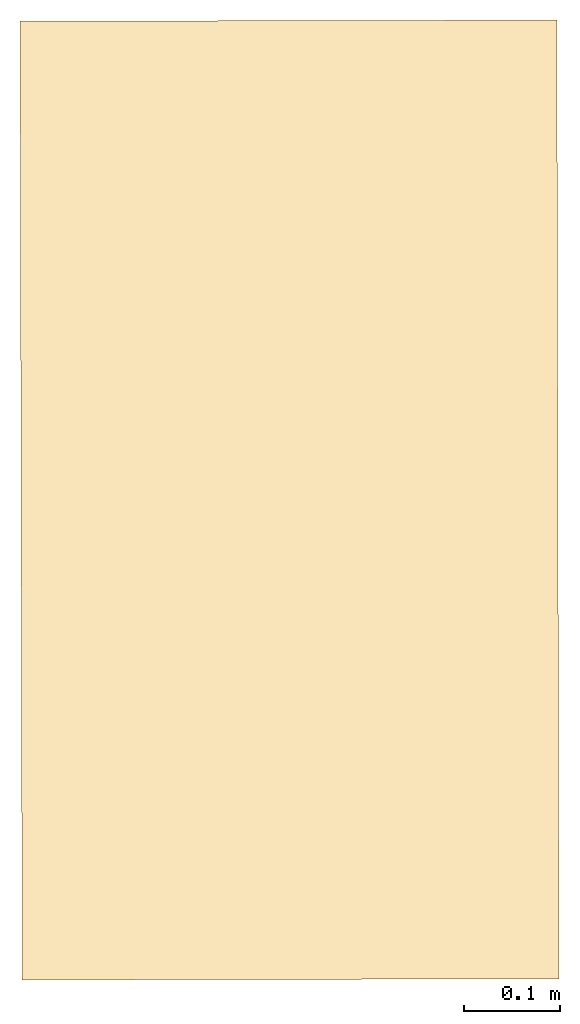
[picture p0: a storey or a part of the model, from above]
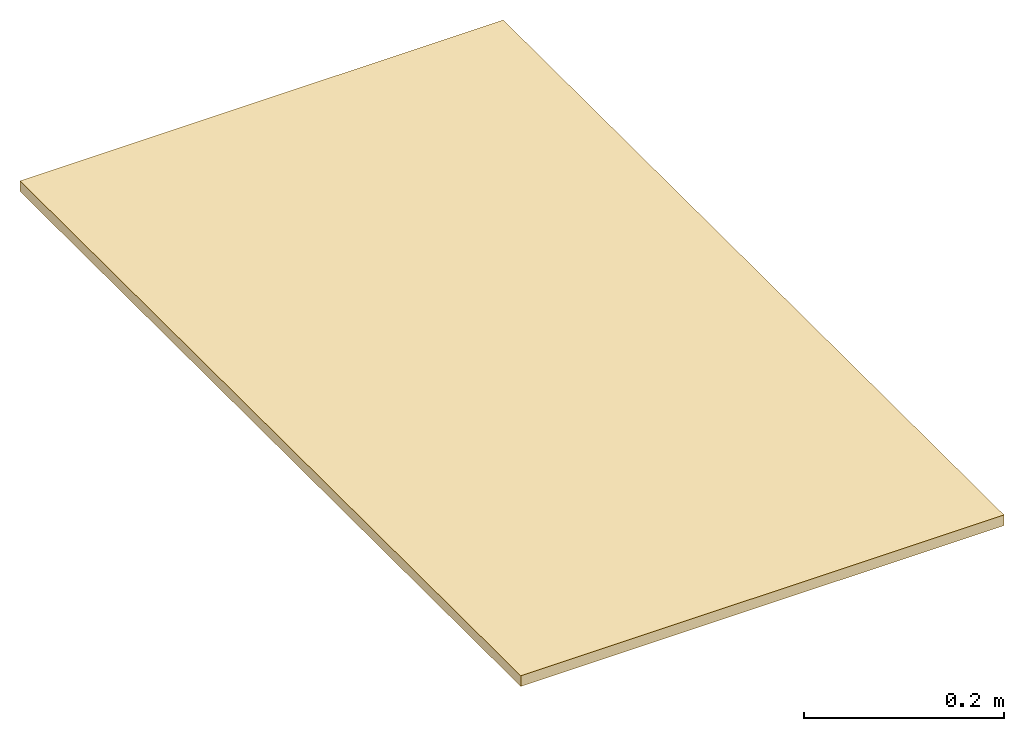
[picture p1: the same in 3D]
Properties of the parts of a building model (IFC4)

# File
Description: ViewDefinition [ReferenceView_V1.2], RevitIdentifiers [ContentGUID: d45b1106-0c7a-46e1-869b-c6a7bbcc7ea5, VersionGUID: 118b0530-1591-4ac2-8939-a10ffb714872, NumberOfSaves: 70], CoordinateReference [CoordinateBase: Internal Origin, ProjectSite: Internal], ExchangeRequirement [Architecture]
File name: 3dv__Detail__15__206+207, WS25 Wall., WS25_A_DE_25_VA_1.ifc
Time: 2025-12-19T14:28:46+01:00
Written by: ODA SDAI 25.12
Made in: Autodesk - Revit 26.3.0.37 (ENU) - 26.4.1.0

# IfcSite, Default
RefLatitude: 45, 45, 37, 23925; RefLongitude: 21, 14, 26, 780090; RefElevation: 0 cm

# IfcBuildingStorey (10)
Name | LongName | Elevation (cm)
B2__ABOVE Slab | B2__ABOVE Slab | -612
B1__ABOVE Slab | B1__ABOVE Slab | -312
L00__ABOVE Slab | L00__ABOVE Slab | -12
L01__ABOVE Slab | L01__ABOVE Slab | 273
L02__ABOVE Slab | L02__ABOVE Slab | 558
L03__ABOVE Slab | L03__ABOVE Slab | 843
L04__ABOVE Slab | L04__ABOVE Slab | 1128
L05__ABOVE Slab | L05__ABOVE Slab | 1413
L06__ABOVE Slab | L06__ABOVE Slab | 1698
L07__ABOVE Slab | L07__ABOVE Slab | 1983

# IfcBeam: Structural Framing : Leichter Stahl Trockenbau : C 50 x 30 (2)
In: L00__ABOVE Slab
Type - PredefinedType: BEAM; Material: Metal - Steel - 345 MPa

# IfcColumn: Columns : wll__TIMBER CORE__Triqbriq__lb : WS15
In: L00__ABOVE Slab
Type - PredefinedType: COLUMN; Material: <Unnamed>

# IfcColumn: Columns : wll_s__TIMBER BLOCK__Triqbriq, Full Width__wp : WS15 (6)
In: L00__ABOVE Slab
Type - PredefinedType: COLUMN; Material: _MASONRY__Timber Block__Triqbriq, X, _MASONRY__Timber Block__Triqbriq, Y

# IfcColumn: Columns : wll_s__TIMBER BLOCK__Triqbriq, Half Width__wp : WS15 (4)
In: L00__ABOVE Slab
Type - PredefinedType: COLUMN; Material: _MASONRY__Timber Block__Triqbriq, X, _MASONRY__Timber Block__Triqbriq, Y

# IfcCovering: Ceilings : Compound Ceiling : clg__INT COVERING__, GB 1.5cm__12.5(A) 3
In: B2__ABOVE Slab
Type - PredefinedType: CEILING
Classification: A 6.1.2.1 Plafoane gips-carton, placi cu cerinte standard (Uniformat); Material: _WLL & CLG FINISHES__Lime - CEM Plaster

# IfcDistributionPort (8)
Description: Flow; FlowDirection: SOURCEANDSINK; PredefinedType: PIPE; SystemType: HEATING
Name | Group
Port_41198656_0 | Hydronic Supply 2
Port_41198656_1 | Hydronic Supply 2
Port_41198681_0 | Hydronic Supply 1
Port_41198681_1 | Hydronic Supply 1
Port_41598727_0 | Hydronic Supply 3
Port_41598727_1 | Hydronic Supply 3
Port_41598729_0 | Hydronic Supply 4
Port_41598729_1 | Hydronic Supply 4

# IfcDistributionSystem: Hydronic Supply (4)
PredefinedType: HEATING
Name
Hydronic Supply 2
Hydronic Supply 1
Hydronic Supply 3
Hydronic Supply 4

# IfcPipeSegment: Pipes : Pipe Types : Default (4)
In: L00__ABOVE Slab
Name (Pipes : Pipe Types :...) | Group
 Default | Hydronic Supply 2
 Default | Hydronic Supply 1
 Default | Hydronic Supply 3
 Default | Hydronic Supply 4

# IfcSlab: Floors : Floor : flr__INT COVERING__Terrazzo Flooring, WP, Floating CEM Screed, EPS A120 9cm TRIQBRIQ
In: L00__ABOVE Slab
Type - PredefinedType: FLOOR; Material: _FLR COVERING__Terrazzo Tiles, R10, _FLR COVERING__Adhesive-fixed Terrazzo Flooring__CEM C2 S1/S2, _FLR LAYERS__WP Membrane__Syntetic Resin__Mapegum WPS, _FLR LAYERS__Screed, SL 0.5%__Semi-dry CEM, Rc ≥ 22.5 N/mm², _FLR LAYERS__Insulation__EPS 120__Austrotherm EPS A120, _FCD VENT LAYERS__Support Board__OSB 3
Classification: A 8.1.3.2 Pardoseli reci pe suport de sapa flotanta (Uniformat)

# IfcSlab: Floors : Floor : flr__STRUCTURE__Wood Beams 15cm__TriqBriq
In: L00__ABOVE Slab
Type - PredefinedType: FLOOR; Material: _STRUCTURE__Wood
Classification: S 1.2 Plansee si acoperisuri terasa (Uniformat)

# IfcWall: Columns : wll_s__DECOUPLING BEAM__Rectangular__wp : Wood
In: B1__ABOVE Slab
Type - PredefinedType: SOLIDWALL; Material: _STRUCTURE__Wood Solid
Classification: A 1.0.3 (Uniformat)

# IfcWall: Columns : wll_s__TIMBER BLOCK__Triqbriq, Full Width__wp1 : WS25 2 (9)
Type - PredefinedType: SOLIDWALL; Material: Miscellaneous__Timber Block__Triqbriq, Y
Classification: A 1.0.1 (Uniformat)
Name (Columns : wll_s__TIMBER BLOCK__Triqbriq, Full Width__wp1 :...) | In
6 x  WS25 2 | L00__ABOVE Slab
3 x  WS25 2 | B1__ABOVE Slab

# IfcWall: Columns : wll_s__TIMBER BLOCK__Triqbriq, Half Width__wp1 : WS25 2 (6)
Type - PredefinedType: SOLIDWALL; Material: Miscellaneous__Timber Block__Triqbriq, Y
Classification: A 1.0.1 (Uniformat)
Name (Columns : wll_s__TIMBER BLOCK__Triqbriq, Half Width__wp1 :...) | In
4 x  WS25 2 | L00__ABOVE Slab
2 x  WS25 2 | B1__ABOVE Slab

# IfcWall: Walls : Basic Wall : wll__EXT ENCLOSURE__Spritzkork, Wood Insulation 8.4cm__TriqBriq, FS.1
In: L00__ABOVE Slab
Type - PredefinedType: STANDARD; Material: _FCD FINISH__Mineral Render__Combed, H L/O__Capatect Kreativeffekt "Filigrano"__White, _STRUCTURE__Wood Solid, _FCD LAYERS__Insulation__Wood-fiber__Steico
Classification: A 4.3.4.2.1 Pereti exteriori (Uniformat)

# IfcWall: Walls : Basic Wall : wll__INT FINISH__Lime - CEM Plaster 2cm (2)
In: L00__ABOVE Slab
Type - PredefinedType: STANDARD; Material: _WLL & CLG FINISHES__Lime - CEM Plaster
Classification: A 7.1.1 Tencuieli umede (Uniformat)

# IfcWall: Walls : Basic Wall : wll__INT PARTITION__3-Ply Wood 2.7cm__TriqBriq, CI.1
In: L00__ABOVE Slab
Type - PredefinedType: STANDARD
Classification: A 5.4.2 Pereti PAL / MDF (Uniformat); Material: _FCD VENT LAYERS__Support Board__3-Layered Wood Board

# IfcWall: Walls : Basic Wall : wll__INT SHAFT__GB, Indep 7.5cm__12.5(H2+A) + CW50@60 / GW50
In: L00__ABOVE Slab
Type - PredefinedType: STANDARD; Material: _PB__GB__Moisture Resistant__Type H2, _PB__GB__Standard__Type A, _PB STUDS & ANC__MTL Studs__50mm__CW 50@60 / GW50
Classification: A 5.3.2.2 Tencuieli uscate gips-carton, placi cu cerinte de rezistenta la umiditate (Uniformat)

# IfcWall: Walls : Basic Wall : wll__INT SHAFT__GB, Indep 7.5cm__12.5(H2+A) + CW50@60 / GW50 2
In: L00__ABOVE Slab
Type - PredefinedType: STANDARD
Classification: A 5.3.2.2 Tencuieli uscate gips-carton, placi cu cerinte de rezistenta la umiditate (Uniformat); Material: _PB STUDS & ANC__MTL Studs__50mm__CW 50@60 / GW50

# IfcWall: Walls : Basic Wall : wll__INT TILING__Ceramic Tiling 2.75cm
In: L00__ABOVE Slab
Type - PredefinedType: STANDARD; Material: _WLL & CLG FINISHES__Ceramic Tiles, _WLL & CLG FINISHES__Adhesive-fixed Ceramic Tiling__CEM C2 S1/S2, _PB__GB__Standard__Type A
Classification: A 7.1.4.1 Placari murale in sistem lipit (Uniformat)

# IfcWall: Walls : Basic Wall : wll__UNCLASSIFIED__Ceramic Tiling 1.5cm__SmartCube (2)
In: L00__ABOVE Slab
Type - PredefinedType: STANDARD; Material: _WLL & CLG FINISHES__Ceramic Tiles, _WLL & CLG FINISHES__Adhesive-fixed Ceramic Tiling__CEM C2 S1/S2
Classification: N NECLASIFICAT (Uniformat)

# IfcWall: Walls : Basic Wall : wll__UNCLASSIFIED__Randdämmstreifen 1.5cm
In: L00__ABOVE Slab
Type - PredefinedType: STANDARD; Material: _FCD LAYERS__Insulation__EPS 120__Austrotherm EPS A120
Classification: N NECLASIFICAT (Uniformat)
